VERSION 5.8 ;
BUSBITCHARS "[]" ;
DIVIDERCHAR "/" ;
UNITS
    DATABASE MICRONS 2000 ;
END UNITS

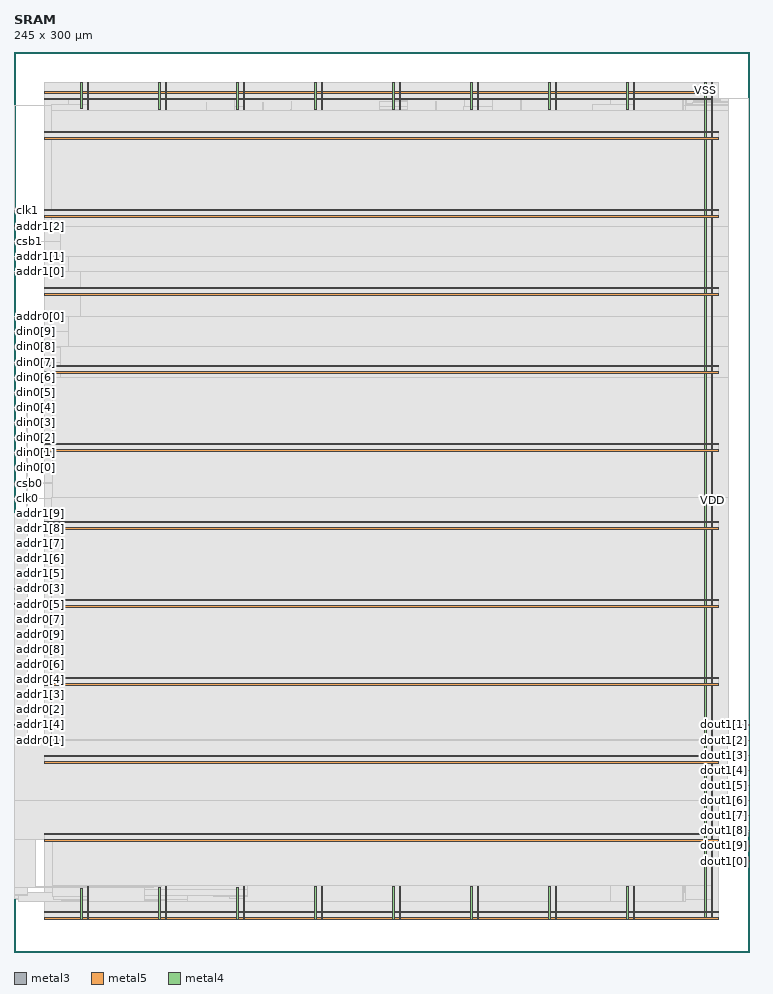
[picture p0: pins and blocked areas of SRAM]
MACRO SRAM
  FOREIGN SRAM 0 0 ;
  CLASS BLOCK ;
  SIZE 245 BY 300 ;
  PIN addr0[0]
    DIRECTION INPUT ;
    USE SIGNAL ;
    PORT
      LAYER metal3 ;
        RECT  0 211.715 0.07 211.785 ;
    END
  END addr0[0]
  PIN addr0[1]
    DIRECTION INPUT ;
    USE SIGNAL ;
    PORT
      LAYER metal3 ;
        RECT  0 70.595 0.07 70.665 ;
    END
  END addr0[1]
  PIN addr0[2]
    DIRECTION INPUT ;
    USE SIGNAL ;
    PORT
      LAYER metal3 ;
        RECT  0 80.675 0.07 80.745 ;
    END
  END addr0[2]
  PIN addr0[3]
    DIRECTION INPUT ;
    USE SIGNAL ;
    PORT
      LAYER metal3 ;
        RECT  0 120.995 0.07 121.065 ;
    END
  END addr0[3]
  PIN addr0[4]
    DIRECTION INPUT ;
    USE SIGNAL ;
    PORT
      LAYER metal3 ;
        RECT  0 90.755 0.07 90.825 ;
    END
  END addr0[4]
  PIN addr0[5]
    DIRECTION INPUT ;
    USE SIGNAL ;
    PORT
      LAYER metal3 ;
        RECT  0 115.955 0.07 116.025 ;
    END
  END addr0[5]
  PIN addr0[6]
    DIRECTION INPUT ;
    USE SIGNAL ;
    PORT
      LAYER metal3 ;
        RECT  0 95.795 0.07 95.865 ;
    END
  END addr0[6]
  PIN addr0[7]
    DIRECTION INPUT ;
    USE SIGNAL ;
    PORT
      LAYER metal3 ;
        RECT  0 110.915 0.07 110.985 ;
    END
  END addr0[7]
  PIN addr0[8]
    DIRECTION INPUT ;
    USE SIGNAL ;
    PORT
      LAYER metal3 ;
        RECT  0 100.835 0.07 100.905 ;
    END
  END addr0[8]
  PIN addr0[9]
    DIRECTION INPUT ;
    USE SIGNAL ;
    PORT
      LAYER metal3 ;
        RECT  0 105.875 0.07 105.945 ;
    END
  END addr0[9]
  PIN addr1[0]
    DIRECTION INPUT ;
    USE SIGNAL ;
    PORT
      LAYER metal3 ;
        RECT  0 226.835 0.07 226.905 ;
    END
  END addr1[0]
  PIN addr1[1]
    DIRECTION INPUT ;
    USE SIGNAL ;
    PORT
      LAYER metal3 ;
        RECT  0 231.875 0.07 231.945 ;
    END
  END addr1[1]
  PIN addr1[2]
    DIRECTION INPUT ;
    USE SIGNAL ;
    PORT
      LAYER metal3 ;
        RECT  0 241.955 0.07 242.025 ;
    END
  END addr1[2]
  PIN addr1[3]
    DIRECTION INPUT ;
    USE SIGNAL ;
    PORT
      LAYER metal3 ;
        RECT  0 85.715 0.07 85.785 ;
    END
  END addr1[3]
  PIN addr1[4]
    DIRECTION INPUT ;
    USE SIGNAL ;
    PORT
      LAYER metal3 ;
        RECT  0 75.635 0.07 75.705 ;
    END
  END addr1[4]
  PIN addr1[5]
    DIRECTION INPUT ;
    USE SIGNAL ;
    PORT
      LAYER metal3 ;
        RECT  0 126.035 0.07 126.105 ;
    END
  END addr1[5]
  PIN addr1[6]
    DIRECTION INPUT ;
    USE SIGNAL ;
    PORT
      LAYER metal3 ;
        RECT  0 131.075 0.07 131.145 ;
    END
  END addr1[6]
  PIN addr1[7]
    DIRECTION INPUT ;
    USE SIGNAL ;
    PORT
      LAYER metal3 ;
        RECT  0 136.115 0.07 136.185 ;
    END
  END addr1[7]
  PIN addr1[8]
    DIRECTION INPUT ;
    USE SIGNAL ;
    PORT
      LAYER metal3 ;
        RECT  0 141.155 0.07 141.225 ;
    END
  END addr1[8]
  PIN addr1[9]
    DIRECTION INPUT ;
    USE SIGNAL ;
    PORT
      LAYER metal3 ;
        RECT  0 146.195 0.07 146.265 ;
    END
  END addr1[9]
  PIN clk0
    DIRECTION INPUT ;
    USE SIGNAL ;
    PORT
      LAYER metal3 ;
        RECT  0 151.235 0.07 151.305 ;
    END
  END clk0
  PIN clk1
    DIRECTION INPUT ;
    USE SIGNAL ;
    PORT
      LAYER metal3 ;
        RECT  0 246.995 0.07 247.065 ;
    END
  END clk1
  PIN csb0
    DIRECTION INPUT ;
    USE SIGNAL ;
    PORT
      LAYER metal3 ;
        RECT  0 156.275 0.07 156.345 ;
    END
  END csb0
  PIN csb1
    DIRECTION INPUT ;
    USE SIGNAL ;
    PORT
      LAYER metal3 ;
        RECT  0 236.915 0.07 236.985 ;
    END
  END csb1
  PIN din0[0]
    DIRECTION INPUT ;
    USE SIGNAL ;
    PORT
      LAYER metal3 ;
        RECT  0 161.315 0.07 161.385 ;
    END
  END din0[0]
  PIN din0[1]
    DIRECTION INPUT ;
    USE SIGNAL ;
    PORT
      LAYER metal3 ;
        RECT  0 166.355 0.07 166.425 ;
    END
  END din0[1]
  PIN din0[2]
    DIRECTION INPUT ;
    USE SIGNAL ;
    PORT
      LAYER metal3 ;
        RECT  0 171.395 0.07 171.465 ;
    END
  END din0[2]
  PIN din0[3]
    DIRECTION INPUT ;
    USE SIGNAL ;
    PORT
      LAYER metal3 ;
        RECT  0 176.435 0.07 176.505 ;
    END
  END din0[3]
  PIN din0[4]
    DIRECTION INPUT ;
    USE SIGNAL ;
    PORT
      LAYER metal3 ;
        RECT  0 181.475 0.07 181.545 ;
    END
  END din0[4]
  PIN din0[5]
    DIRECTION INPUT ;
    USE SIGNAL ;
    PORT
      LAYER metal3 ;
        RECT  0 186.515 0.07 186.585 ;
    END
  END din0[5]
  PIN din0[6]
    DIRECTION INPUT ;
    USE SIGNAL ;
    PORT
      LAYER metal3 ;
        RECT  0 191.555 0.07 191.625 ;
    END
  END din0[6]
  PIN din0[7]
    DIRECTION INPUT ;
    USE SIGNAL ;
    PORT
      LAYER metal3 ;
        RECT  0 196.595 0.07 196.665 ;
    END
  END din0[7]
  PIN din0[8]
    DIRECTION INPUT ;
    USE SIGNAL ;
    PORT
      LAYER metal3 ;
        RECT  0 201.635 0.07 201.705 ;
    END
  END din0[8]
  PIN din0[9]
    DIRECTION INPUT ;
    USE SIGNAL ;
    PORT
      LAYER metal3 ;
        RECT  0 206.675 0.07 206.745 ;
    END
  END din0[9]
  PIN dout1[0]
    DIRECTION OUTPUT ;
    USE SIGNAL ;
    PORT
      LAYER metal3 ;
        RECT  244.93 30.275 245 30.345 ;
    END
  END dout1[0]
  PIN dout1[1]
    DIRECTION OUTPUT ;
    USE SIGNAL ;
    PORT
      LAYER metal3 ;
        RECT  244.93 75.635 245 75.705 ;
    END
  END dout1[1]
  PIN dout1[2]
    DIRECTION OUTPUT ;
    USE SIGNAL ;
    PORT
      LAYER metal3 ;
        RECT  244.93 70.595 245 70.665 ;
    END
  END dout1[2]
  PIN dout1[3]
    DIRECTION OUTPUT ;
    USE SIGNAL ;
    PORT
      LAYER metal3 ;
        RECT  244.93 65.555 245 65.625 ;
    END
  END dout1[3]
  PIN dout1[4]
    DIRECTION OUTPUT ;
    USE SIGNAL ;
    PORT
      LAYER metal3 ;
        RECT  244.93 60.515 245 60.585 ;
    END
  END dout1[4]
  PIN dout1[5]
    DIRECTION OUTPUT ;
    USE SIGNAL ;
    PORT
      LAYER metal3 ;
        RECT  244.93 55.475 245 55.545 ;
    END
  END dout1[5]
  PIN dout1[6]
    DIRECTION OUTPUT ;
    USE SIGNAL ;
    PORT
      LAYER metal3 ;
        RECT  244.93 50.435 245 50.505 ;
    END
  END dout1[6]
  PIN dout1[7]
    DIRECTION OUTPUT ;
    USE SIGNAL ;
    PORT
      LAYER metal3 ;
        RECT  244.93 45.395 245 45.465 ;
    END
  END dout1[7]
  PIN dout1[8]
    DIRECTION OUTPUT ;
    USE SIGNAL ;
    PORT
      LAYER metal3 ;
        RECT  244.93 40.355 245 40.425 ;
    END
  END dout1[8]
  PIN dout1[9]
    DIRECTION OUTPUT ;
    USE SIGNAL ;
    PORT
      LAYER metal3 ;
        RECT  244.93 35.315 245 35.385 ;
    END
  END dout1[9]
  PIN VSS
    DIRECTION INOUT ;
    USE GROUND ;
    PORT
      LAYER metal5 ;
        RECT  10.07 286.26 232.92 286.76 ;
        RECT  10.07 270.95 234.84 271.45 ;
        RECT  10.07 244.95 234.84 245.45 ;
        RECT  10.07 218.95 234.84 219.45 ;
        RECT  10.07 192.95 234.84 193.45 ;
        RECT  10.07 166.95 234.84 167.45 ;
        RECT  10.07 140.95 234.84 141.45 ;
        RECT  10.07 114.95 234.84 115.45 ;
        RECT  10.07 88.95 234.84 89.45 ;
        RECT  10.07 62.95 234.84 63.45 ;
        RECT  10.07 36.95 234.84 37.45 ;
        RECT  10.07 10.95 234.84 11.45 ;
      LAYER metal4 ;
        RECT  230.32 10.95 230.82 289.84 ;
        RECT  204.32 280.82 204.82 289.84 ;
        RECT  204.32 10.95 204.82 21.79 ;
        RECT  178.32 280.82 178.82 289.84 ;
        RECT  178.32 10.95 178.82 21.79 ;
        RECT  152.32 280.82 152.82 289.84 ;
        RECT  152.32 10.95 152.82 21.79 ;
        RECT  126.32 280.82 126.82 289.84 ;
        RECT  126.32 10.95 126.82 21.79 ;
        RECT  100.32 280.82 100.82 289.84 ;
        RECT  100.32 10.95 100.82 21.79 ;
        RECT  74.32 280.82 74.82 289.84 ;
        RECT  74.32 10.95 74.82 21.65 ;
        RECT  48.32 280.82 48.82 289.84 ;
        RECT  48.32 10.95 48.82 21.65 ;
        RECT  22.32 281.32 22.82 289.84 ;
        RECT  22.32 10.95 22.82 21.29 ;
    END
  END VSS
  PIN VDD
    DIRECTION INOUT ;
    USE POWER ;
    PORT
      LAYER metal5 ;
        RECT  10.07 284.02 232.92 284.52 ;
        RECT  10.07 273.05 234.84 273.55 ;
        RECT  10.07 247.05 234.84 247.55 ;
        RECT  10.07 221.05 234.84 221.55 ;
        RECT  10.07 195.05 234.84 195.55 ;
        RECT  10.07 169.05 234.84 169.55 ;
        RECT  10.07 143.05 234.84 143.55 ;
        RECT  10.07 117.05 234.84 117.55 ;
        RECT  10.07 91.05 234.84 91.55 ;
        RECT  10.07 65.05 234.84 65.55 ;
        RECT  10.07 39.05 234.84 39.55 ;
        RECT  10.07 13.05 234.84 13.55 ;
      LAYER metal4 ;
        RECT  232.42 11.16 232.92 289.87 ;
        RECT  206.42 280.82 206.92 289.87 ;
        RECT  206.42 11.16 206.92 21.79 ;
        RECT  180.42 280.82 180.92 289.87 ;
        RECT  180.42 11.16 180.92 21.79 ;
        RECT  154.42 280.82 154.92 289.87 ;
        RECT  154.42 11.16 154.92 21.79 ;
        RECT  128.42 280.82 128.92 289.87 ;
        RECT  128.42 11.16 128.92 21.79 ;
        RECT  102.42 280.82 102.92 289.87 ;
        RECT  102.42 11.16 102.92 21.79 ;
        RECT  76.42 280.82 76.92 289.87 ;
        RECT  76.42 11.16 76.92 21.79 ;
        RECT  50.42 280.82 50.92 289.87 ;
        RECT  50.42 11.16 50.92 21.79 ;
        RECT  24.42 280.82 24.92 289.87 ;
        RECT  24.42 11.16 24.92 21.79 ;
    END
  END VDD
  OBS
    LAYER metal1 ;
     RECT  10.07 11.115 234.84 289.885 ;
    LAYER metal2 ;
     RECT  22.34 11.13 22.8 12.53 ;
     RECT  48.34 11.13 48.8 12.53 ;
     RECT  74.34 11.13 74.8 12.53 ;
     RECT  100.34 11.13 100.8 12.53 ;
     RECT  126.34 11.13 126.8 12.53 ;
     RECT  152.34 11.13 152.8 12.53 ;
     RECT  178.34 11.13 178.8 12.53 ;
     RECT  204.34 11.13 204.8 12.53 ;
     RECT  230.34 11.13 230.8 12.53 ;
     RECT  223.12 17.92 223.19 19.32 ;
     RECT  34.26 19.46 34.33 19.6 ;
     RECT  34.26 19.6 34.52 19.635 ;
     RECT  22.34 12.53 24.9 22.2 ;
     RECT  34.26 19.635 34.71 22.2 ;
     RECT  48.34 12.53 50.9 22.2 ;
     RECT  74.34 12.53 76.9 22.2 ;
     RECT  100.34 12.53 102.9 22.2 ;
     RECT  126.34 12.53 128.9 22.2 ;
     RECT  152.34 12.53 154.9 22.2 ;
     RECT  178.34 12.53 180.9 22.2 ;
     RECT  204.34 12.53 206.9 22.2 ;
     RECT  223.12 19.32 223.38 22.2 ;
     RECT  22.295 22.2 223.38 40.81 ;
     RECT  22.295 40.81 223.19 42.84 ;
     RECT  22.295 42.84 222.96 280.41 ;
     RECT  22.34 280.41 24.9 288.47 ;
     RECT  48.34 280.41 50.9 288.47 ;
     RECT  74.34 280.41 76.9 288.47 ;
     RECT  100.34 280.41 102.9 288.47 ;
     RECT  126.34 280.41 128.9 288.47 ;
     RECT  152.34 280.41 154.9 288.47 ;
     RECT  178.34 280.41 180.9 288.47 ;
     RECT  204.34 280.41 206.9 288.47 ;
     RECT  230.34 12.53 232.9 288.47 ;
     RECT  24.44 288.47 24.9 289.87 ;
     RECT  50.44 288.47 50.9 289.87 ;
     RECT  76.44 288.47 76.9 289.87 ;
     RECT  102.44 288.47 102.9 289.87 ;
     RECT  128.44 288.47 128.9 289.87 ;
     RECT  154.44 288.47 154.9 289.87 ;
     RECT  180.44 288.47 180.9 289.87 ;
     RECT  206.44 288.47 206.9 289.87 ;
     RECT  232.44 288.47 232.9 289.87 ;
    LAYER metal3 ;
     RECT  0.025 146.195 0.165 146.265 ;
     RECT  0.025 246.995 0.165 247.065 ;
     RECT  0.025 19.355 0.305 19.425 ;
     RECT  0.035 141.155 0.445 141.225 ;
     RECT  0.305 17.955 0.585 19.425 ;
     RECT  0.035 136.115 0.725 136.185 ;
     RECT  0.585 17.955 0.865 19.845 ;
     RECT  0.035 131.075 1.005 131.145 ;
     RECT  0.035 126.035 1.285 126.105 ;
     RECT  0.865 17.675 1.425 19.845 ;
     RECT  0.035 85.715 1.565 85.785 ;
     RECT  0.035 181.475 4.365 181.545 ;
     RECT  0.035 70.595 7.165 70.665 ;
     RECT  0.025 282.135 12.625 282.205 ;
     RECT  0.035 151.235 12.765 151.305 ;
     RECT  0.035 241.955 12.765 242.025 ;
     RECT  0.035 191.555 13.045 191.625 ;
     RECT  0.035 161.315 13.325 161.385 ;
     RECT  0.035 80.675 13.605 80.745 ;
     RECT  0.035 201.635 15.565 201.705 ;
     RECT  0.035 231.875 15.565 231.945 ;
     RECT  0.035 171.395 15.845 171.465 ;
     RECT  12.625 37.415 15.985 37.485 ;
     RECT  0.035 156.275 16.125 156.345 ;
     RECT  0.035 120.995 16.405 121.065 ;
     RECT  0.035 90.755 17.945 90.825 ;
     RECT  0.035 115.955 18.085 116.025 ;
     RECT  12.625 282.135 18.225 282.625 ;
     RECT  0.035 211.715 18.365 211.785 ;
     RECT  0.035 226.835 18.365 226.905 ;
     RECT  0.035 206.675 18.645 206.745 ;
     RECT  0.035 236.915 18.645 236.985 ;
     RECT  0.035 196.595 18.925 196.665 ;
     RECT  0.035 186.515 19.205 186.585 ;
     RECT  1.425 16.975 19.345 19.845 ;
     RECT  0.035 176.435 19.485 176.505 ;
     RECT  0.035 95.795 19.905 95.865 ;
     RECT  0.035 100.835 20.185 100.905 ;
     RECT  17.945 90.755 21.62 92.785 ;
     RECT  19.905 95.795 21.62 97.685 ;
     RECT  19.345 16.975 22.155 19.985 ;
     RECT  15.985 37.135 22.155 37.485 ;
     RECT  16.265 87.675 22.155 87.745 ;
     RECT  21.62 90.755 22.155 97.685 ;
     RECT  20.185 100.835 22.155 102.585 ;
     RECT  18.225 282.135 22.155 284.725 ;
     RECT  22.155 16.975 22.295 22.76 ;
     RECT  22.155 37.1 22.295 37.485 ;
     RECT  0.035 75.635 22.295 75.705 ;
     RECT  22.155 87.67 22.295 102.63 ;
     RECT  0.035 105.875 22.295 105.945 ;
     RECT  0.035 110.915 22.295 110.985 ;
     RECT  0.035 166.355 22.295 166.425 ;
     RECT  22.155 279.85 22.295 284.725 ;
     RECT  22.295 16.975 22.34 284.725 ;
     RECT  22.34 11.13 22.8 288.47 ;
     RECT  22.8 12.53 24.44 288.47 ;
     RECT  24.44 12.53 24.9 289.87 ;
     RECT  24.9 16.975 48.34 284.725 ;
     RECT  48.34 11.13 48.8 288.47 ;
     RECT  48.8 12.53 50.44 288.47 ;
     RECT  50.44 12.53 50.9 289.87 ;
     RECT  50.9 16.975 74.34 284.725 ;
     RECT  74.34 11.13 74.8 288.47 ;
     RECT  74.8 12.53 76.44 288.47 ;
     RECT  76.44 12.53 76.9 289.87 ;
     RECT  76.9 16.975 100.34 284.725 ;
     RECT  100.34 11.13 100.8 288.47 ;
     RECT  100.8 12.53 102.44 288.47 ;
     RECT  102.44 12.53 102.9 289.87 ;
     RECT  102.9 16.975 126.34 284.725 ;
     RECT  126.34 11.13 126.8 288.47 ;
     RECT  126.8 12.53 128.44 288.47 ;
     RECT  128.44 12.53 128.9 289.87 ;
     RECT  128.9 16.975 152.34 284.725 ;
     RECT  152.34 11.13 152.8 288.47 ;
     RECT  152.8 12.53 154.44 288.47 ;
     RECT  154.44 12.53 154.9 289.87 ;
     RECT  154.9 16.975 178.34 284.725 ;
     RECT  178.34 11.13 178.8 288.47 ;
     RECT  178.8 12.53 180.44 288.47 ;
     RECT  180.44 12.53 180.9 289.87 ;
     RECT  180.9 16.975 198.965 284.725 ;
     RECT  198.965 16.975 204.34 284.585 ;
     RECT  204.34 11.13 204.8 288.47 ;
     RECT  204.8 12.53 206.44 288.47 ;
     RECT  206.44 12.53 206.9 289.87 ;
     RECT  206.9 16.975 222.96 284.585 ;
     RECT  222.96 16.975 223.1 22.76 ;
     RECT  222.96 40.705 223.1 55.7 ;
     RECT  222.96 264.705 223.1 265.08 ;
     RECT  222.96 279.85 223.1 284.585 ;
     RECT  223.1 40.705 223.225 42.805 ;
     RECT  223.225 40.705 223.415 40.775 ;
     RECT  223.1 264.775 223.57 265.01 ;
     RECT  223.1 16.975 223.885 19.845 ;
     RECT  223.1 54.915 223.885 54.985 ;
     RECT  223.57 264.775 223.885 264.985 ;
     RECT  223.1 282.135 223.885 284.585 ;
     RECT  223.1 45.675 224.165 52.045 ;
     RECT  223.885 264.915 224.165 264.985 ;
     RECT  223.885 282.275 224.165 284.585 ;
     RECT  224.165 45.675 224.445 50.085 ;
     RECT  223.885 17.675 224.725 19.845 ;
     RECT  224.445 45.675 224.725 47.985 ;
     RECT  224.725 19.775 225.005 19.845 ;
     RECT  224.725 45.675 225.005 45.745 ;
     RECT  224.165 282.975 226.405 284.585 ;
     RECT  226.265 30.275 230.34 30.345 ;
     RECT  226.545 35.315 230.34 35.385 ;
     RECT  226.825 45.395 230.34 45.465 ;
     RECT  227.105 55.475 230.34 55.545 ;
     RECT  227.385 65.555 230.34 65.625 ;
     RECT  226.405 283.115 230.34 284.585 ;
     RECT  230.34 11.13 230.8 288.47 ;
     RECT  230.8 12.53 232.44 288.47 ;
     RECT  232.44 12.53 232.9 289.87 ;
     RECT  232.9 283.115 235.365 284.585 ;
     RECT  235.365 283.115 238.165 284.445 ;
     RECT  238.165 284.375 244.885 284.445 ;
     RECT  232.9 30.275 244.965 30.345 ;
     RECT  232.9 35.315 244.965 35.385 ;
     RECT  244.745 40.355 244.965 40.425 ;
     RECT  232.9 45.395 244.965 45.465 ;
     RECT  237.745 50.435 244.965 50.505 ;
     RECT  232.9 55.475 244.965 55.545 ;
     RECT  232.9 60.515 244.965 60.585 ;
     RECT  232.9 65.555 244.965 65.625 ;
     RECT  238.025 70.595 244.965 70.665 ;
     RECT  232.9 75.635 244.965 75.705 ;
    LAYER metal4 ;
     RECT  22.32 10.95 22.82 11.16 ;
     RECT  48.32 10.95 48.82 11.16 ;
     RECT  74.32 10.95 74.82 11.16 ;
     RECT  100.32 10.95 100.82 11.16 ;
     RECT  126.32 10.95 126.82 11.16 ;
     RECT  152.32 10.95 152.82 11.16 ;
     RECT  178.32 10.95 178.82 11.16 ;
     RECT  204.32 10.95 204.82 11.16 ;
     RECT  230.32 10.95 230.82 11.16 ;
     RECT  15.705 17.08 15.845 17.22 ;
     RECT  22.32 11.16 24.92 17.22 ;
     RECT  48.32 11.16 50.92 17.22 ;
     RECT  43.425 17.22 50.92 17.36 ;
     RECT  57.705 17.08 57.845 17.36 ;
     RECT  15.705 17.22 24.92 17.5 ;
     RECT  1.425 16.94 1.565 17.64 ;
     RECT  223.745 16.94 223.885 17.64 ;
     RECT  230.32 11.16 232.92 17.64 ;
     RECT  74.32 11.16 76.92 17.78 ;
     RECT  0.865 17.64 1.565 17.92 ;
     RECT  71.985 17.78 76.92 18.34 ;
     RECT  13.185 17.5 24.92 18.48 ;
     RECT  66.385 18.34 76.92 18.62 ;
     RECT  0.305 17.92 1.565 18.9 ;
     RECT  43.425 17.36 57.845 18.9 ;
     RECT  66.385 18.62 77.725 18.9 ;
     RECT  0.305 18.9 4.365 19.32 ;
     RECT  43.425 18.9 77.725 20.72 ;
     RECT  0.025 19.32 4.365 21.56 ;
     RECT  223.745 17.64 232.92 22.06 ;
     RECT  12.905 18.48 24.92 22.2 ;
     RECT  43.425 20.72 77.885 22.2 ;
     RECT  100.32 11.16 102.92 22.2 ;
     RECT  126.32 11.16 128.92 22.2 ;
     RECT  152.32 11.16 154.92 22.2 ;
     RECT  178.32 11.16 180.92 22.2 ;
     RECT  204.32 11.16 206.92 22.2 ;
     RECT  222.4 22.06 232.92 22.2 ;
     RECT  0.025 21.56 7.165 37.38 ;
     RECT  12.905 22.2 232.92 37.38 ;
     RECT  0.025 37.38 232.92 50.4 ;
     RECT  0.025 50.4 237.885 70.56 ;
     RECT  0.025 70.56 238.165 70.7 ;
     RECT  0.025 70.7 4.365 146.3 ;
     RECT  12.625 70.7 238.165 151.34 ;
     RECT  4.225 146.3 4.365 181.58 ;
     RECT  12.905 151.34 238.165 191.66 ;
     RECT  15.425 191.66 238.165 201.74 ;
     RECT  18.225 201.74 238.165 211.82 ;
     RECT  22.155 211.82 238.165 226.8 ;
     RECT  18.225 226.8 238.165 231.84 ;
     RECT  15.425 231.84 238.165 241.92 ;
     RECT  12.625 241.92 238.165 280.41 ;
     RECT  222.4 280.41 238.165 280.55 ;
     RECT  92.285 280.41 92.565 280.98 ;
     RECT  121.745 280.41 131.285 280.98 ;
     RECT  168.745 280.41 169.005 280.98 ;
     RECT  64.085 280.41 64.285 281.82 ;
     RECT  73.485 280.41 76.92 281.82 ;
     RECT  82.885 280.41 83.045 281.82 ;
     RECT  121.825 280.98 131.285 281.82 ;
     RECT  140.545 280.41 140.725 281.82 ;
     RECT  149.945 280.41 159.485 281.82 ;
     RECT  0.025 246.96 0.165 282.24 ;
     RECT  223.745 280.55 238.165 282.24 ;
     RECT  224.025 282.24 238.165 282.38 ;
     RECT  192.945 280.41 206.92 282.52 ;
     RECT  12.625 280.41 24.92 282.66 ;
     RECT  192.945 282.52 193.085 282.66 ;
     RECT  64.145 281.82 64.285 283.08 ;
     RECT  226.265 282.38 238.165 283.08 ;
     RECT  82.905 281.82 83.045 283.22 ;
     RECT  226.545 283.08 238.165 283.22 ;
     RECT  92.425 280.98 92.565 283.36 ;
     RECT  121.825 281.82 131.205 283.5 ;
     RECT  140.585 281.82 140.725 283.64 ;
     RECT  226.545 283.22 237.885 283.64 ;
     RECT  126.32 283.5 131.205 283.78 ;
     RECT  168.865 280.98 169.005 283.92 ;
     RECT  226.545 283.64 235.365 283.92 ;
     RECT  150.105 281.82 159.485 284.06 ;
     RECT  226.825 283.92 235.365 284.06 ;
     RECT  152.32 284.06 159.485 284.48 ;
     RECT  244.745 40.32 244.885 284.48 ;
     RECT  73.665 281.82 76.92 284.62 ;
     RECT  230.32 284.06 235.365 284.62 ;
     RECT  18.225 282.66 24.92 284.76 ;
     RECT  198.825 282.52 206.92 284.76 ;
     RECT  22.32 284.76 24.92 289.84 ;
     RECT  48.32 280.41 50.92 289.84 ;
     RECT  74.32 284.62 76.92 289.84 ;
     RECT  100.32 280.41 102.92 289.84 ;
     RECT  126.32 283.78 128.92 289.84 ;
     RECT  152.32 284.48 154.92 289.84 ;
     RECT  178.32 280.41 180.92 289.84 ;
     RECT  204.32 284.76 206.92 289.84 ;
     RECT  230.32 284.62 232.92 289.84 ;
     RECT  24.42 289.84 24.92 289.87 ;
     RECT  50.42 289.84 50.92 289.87 ;
     RECT  76.42 289.84 76.92 289.87 ;
     RECT  102.42 289.84 102.92 289.87 ;
     RECT  128.42 289.84 128.92 289.87 ;
     RECT  154.42 289.84 154.92 289.87 ;
     RECT  180.42 289.84 180.92 289.87 ;
     RECT  206.42 289.84 206.92 289.87 ;
     RECT  232.42 289.84 232.92 289.87 ;
    LAYER metal5 ;
     RECT  7.025 21.56 13.465 21.7 ;
     RECT  13.465 21.56 46.425 21.98 ;
     RECT  46.425 21.84 49.025 21.98 ;
     RECT  49.025 21.84 49.165 22.2 ;
     RECT  49.165 22.06 49.285 22.2 ;
     RECT  10.07 284.02 232.92 286.76 ;
     RECT  10.07 10.95 234.84 13.55 ;
     RECT  10.07 36.95 234.84 39.55 ;
     RECT  10.07 62.95 234.84 65.55 ;
     RECT  10.07 88.95 234.84 91.55 ;
     RECT  10.07 114.95 234.84 117.55 ;
     RECT  10.07 140.95 234.84 143.55 ;
     RECT  10.07 166.95 234.84 169.55 ;
     RECT  10.07 192.95 234.84 195.55 ;
     RECT  10.07 218.95 234.84 221.55 ;
     RECT  10.07 244.95 234.84 247.55 ;
     RECT  10.07 270.95 234.84 273.55 ;
  END
END SRAM
END LIBRARY
